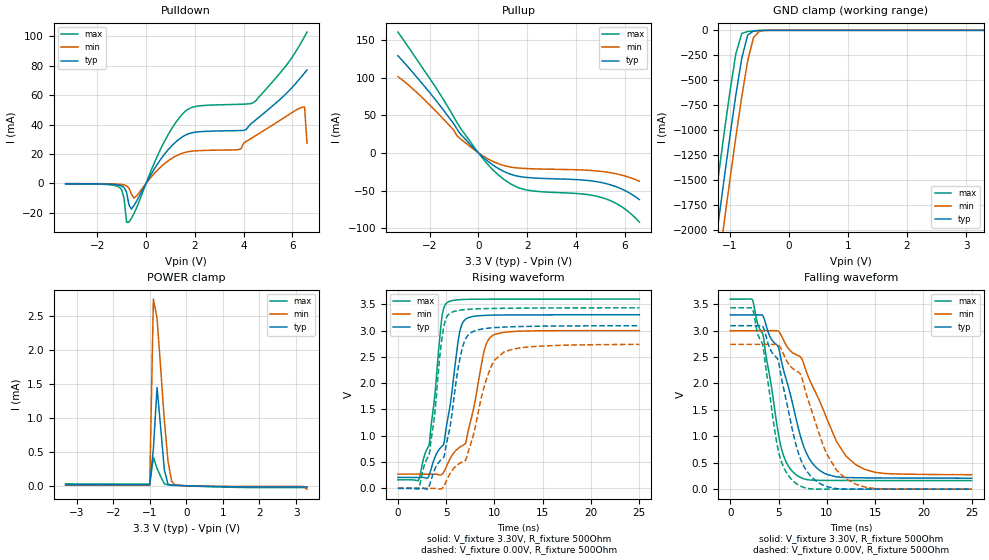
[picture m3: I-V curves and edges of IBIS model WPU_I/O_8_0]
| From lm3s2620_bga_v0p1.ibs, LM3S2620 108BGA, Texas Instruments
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[Model]   WPU_I/O_8_0
Model_type   I/O
Vinl = 1.26
Vinh = 2.04
Vmeas = 1.65
| variable   typ   min   max
C_comp   9.739pF   9.739pF   9.739pF
[Model Spec]
Vinh+   1.91   1.78   2.04
Vinh-   1.90   1.76   2.03
Vinl+   1.40   1.27   1.54
Vinl-   1.39   1.26   1.53
| variable   typ   min   max
[Temperature Range]  25   85   -40
[Voltage Range]   3.3V   3.0V   3.6V
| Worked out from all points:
|   slope of the pulldown table from 0 to 0.495 V, typ, clamps not added: 35.8 ohm
|   slope of the pullup table from 0 to 0.495 V, typ, clamps not added: 35.8 ohm
|   GND clamp passes 1 mA (typ) near -0.48 V on its own axis
|   POWER clamp passes 1 mA (typ) near -0.73 V on its own axis
|   falling waveform, V_fixture 3.30V, R_fixture 500Ohm: 20-80 % time 2.57ns typ, 3.86ns min, 1.79ns max; typ from 3.3 V to 0.208 V
|   rising waveform, V_fixture 3.30V, R_fixture 500Ohm: 20-80 % time 1.44ns typ, 2.05ns min, 1.12ns max; typ from 0.208 V to 3.3 V
|   falling waveform, V_fixture 0.00V, R_fixture 500Ohm: 20-80 % time 2.32ns typ, 3.17ns min, 1.7ns max; typ from 3.09 V to 0 V
|   rising waveform, V_fixture 0.00V, R_fixture 500Ohm: 20-80 % time 1.63ns typ, 2.35ns min, 1.2ns max; typ from 0 V to 3.09 V
[Pulldown]
|  Voltage   I(typ)   I(min)   I(max)
-3.3V     -256.4uA   -145.5uA   -364.3uA
-1.1V     -1.272mA   -586.9uA   -2.565mA
-900mV    -2.884mA   -1.06mA    -10.53mA
-800mV    -5.991mA   -1.669mA   -26.38mA
-700mV    -14.71mA   -3.213mA   -26.31mA
-500mV    -15.24mA   -9.997mA   -20.64mA
600mV     16.38mA    11.14mA    23.43mA
1.5V      31.7mA     20.53mA    47.23mA
3.8V      35.88mA    22.99mA    53.74mA
4.4V      41.81mA    31.48mA    54.88mA
6.5V      75.06mA    51.95mA    99.78mA
6.6V      77.08mA    27.42mA    102.8mA
[Pullup]
|  Voltage   I(typ)   I(min)   I(max)
-3.3V     128.9mA    101.3mA    160.4mA
-2V       80.13mA    63.77mA    99.04mA
-1V       37.9mA     29.83mA    47.32mA
-700mV    23.8mA     17.69mA    31.27mA
300mV     -8.84mA    -6.3mA     -12.15mA
1V        -23.98mA   -16.37mA   -34.08mA
1.5V      -30.12mA   -19.69mA   -44.19mA
2V        -32.71mA   -20.86mA   -49.43mA
4.3V      -36.12mA   -22.8mA    -54.73mA
5.1V      -39.81mA   -24.88mA   -59.77mA
5.9V      -48.4mA    -29.75mA   -72.06mA
6.6V      -62.06mA   -37.61mA   -92.08mA
[GND Clamp]
|  Voltage   I(typ)   I(min)   I(max)
-3.3V     -11.72A    -12.12A    -11.3A
-1.4V     -2.845A    -3.285A    -2.387A
-1.3V     -2.39A     -2.831A    -1.93A
-1.2V     -1.938A    -2.38A     -1.478A
-1.1V     -1.494A    -1.934A    -1.036A
-1V       -1.059A    -1.496A    -610.6mA
-900mV    -645mA     -1.069A    -232.9mA
-800mV    -277.1mA   -664.4mA   -31.6mA
-700mV    -48.56mA   -306.6mA   -12.11mA
-600mV    -5.565mA   -70.2mA    -6.295mA
-500mV    -1.181mA   -7.883mA   -2.191mA
3.3V      2.282nA    6.919uA    -6.845uA
[POWER Clamp]
|  Voltage   I(typ)   I(min)   I(max)
-3.3V     15.18uA    8.315uA    27.48uA
-1V       14.14uA    7.74uA     25.63uA
-900mV    539.2uA    2.746mA    419.4uA
-800mV    1.446mA    2.463mA    255uA
-700mV    851uA      1.726mA    135.8uA
-600mV    231.3uA    957.3uA    27.23uA
-500mV    21.69uA    361.2uA    14.14uA
-400mV    7.764uA    63.51uA    10.49uA
-300mV    5.5uA      6.919uA    7.727uA
3.1V      -16.64uA   -9.947uA   -27.43uA
3.2V      -16.65uA   -12.11uA   -27.44uA
3.3V      -16.65uA   -49.87uA   -27.45uA
[Ramp]
| variable   typ   min   max
dV/dt_f   1.85/2.57n   1.63/3.86n   2.06/1.79n
dV/dt_r   1.86/1.63n   1.64/2.35n   2.06/1.20n
R_load = 500Ohm
[Falling Waveform]
V_fixture = 3.30V
V_fixture_min = 3.00V
V_fixture_max = 3.60V
R_fixture = 500Ohm
|   Time   V(typ)   V(min)   V(max)
0s        3.298V     2.997V     3.597V
2.3ns     3.298V     2.998V     3.585V
3.4ns     3.276V     2.999V     2.915V
5.3ns     2.425V     2.905V     768.3mV
6.8ns     1.342V     2.547V     275.7mV
7.8ns     718.5mV    2.267V     187.4mV
8.9ns     411.5mV    1.807V     167.9mV
11ns      231.5mV    902.7mV    164.8mV
13ns      216.8mV    461.7mV    163.7mV
25ns      208.1mV    273.3mV    162.3mV
[Rising Waveform]
V_fixture = 3.30V
V_fixture_min = 3.00V
V_fixture_max = 3.60V
R_fixture = 500Ohm
|   Time   V(typ)   V(min)   V(max)
0s        207.6mV    270.8mV    162.2mV
2.1ns     207.5mV    270.3mV    146.3mV
3.2ns     232.4mV    270mV      805.7mV
4.5ns     789mV      258.8mV    3.176V
5.1ns     1.262V     447.4mV    3.532V
6.6ns     3.106V     806.1mV    3.588V
7.1ns     3.226V     929.8mV    3.592V
9ns       3.288V     2.662V     3.596V
9.8ns     3.293V     2.906V     3.597V
25ns      3.299V     2.999V     3.598V
[Falling Waveform]
V_fixture = 0.00V
V_fixture_min = 0.00V
V_fixture_max = 0.00V
R_fixture = 500Ohm
|   Time   V(typ)   V(min)   V(max)
0s        3.093V     2.74V      3.433V
2.3ns     3.093V     2.74V      3.421V
3.4ns     3.071V     2.741V     2.706V
5ns       2.413V     2.729V     711.4mV
6.8ns     844mV      2.241V     111.1mV
7.4ns     518mV      2.122V     48.36mV
8.7ns     183.7mV    1.335V     2.419mV
10ns      48.12mV    663.5mV    981.6uV
12ns      1.875mV    192.7mV    82.37uV
25ns      33.93uV    47.46uV    17.48uV
[Rising Waveform]
V_fixture = 0.00V
V_fixture_min = 0.00V
V_fixture_max = 0.00V
R_fixture = 500Ohm
|   Time   V(typ)   V(min)   V(max)
0s        193.9uV    2.805mV    104.1uV
2.1ns     125.6uV    574.4uV    -15.02mV
3.2ns     26.93mV    301.2uV    615.4mV
4.7ns     577.9mV    27.17mV    3.028V
5.4ns     1.177V     280.6mV    3.328V
6.3ns     2.353V     463.7mV    3.383V
7ns       2.839V     531.8mV    3.399V
9.3ns     3.044V     2.145V     3.418V
11ns      3.066V     2.596V     3.423V
25ns      3.092V     2.737V     3.432V
